VERSION 5.7 ;
  NOWIREEXTENSIONATPIN ON ;
  DIVIDERCHAR "/" ;
  BUSBITCHARS "[]" ;
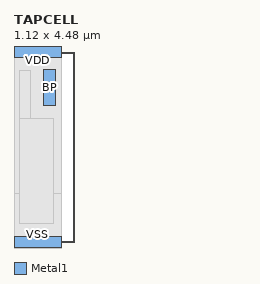
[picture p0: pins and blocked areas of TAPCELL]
MACRO TAPCELL
  CLASS core ;
  FOREIGN TAPCELL ;
  ORIGIN 0.000 0.000 ;
  SIZE 1.120 BY 4.480 ;
  SITE site056um ;
  PIN VSS
    DIRECTION INOUT ;
    USE GROUND ;
    PORT
      LAYER Metal1 ;
        RECT 0.000 -0.140 1.120 0.140 ;
    END
  END VSS
  PIN VDD
    DIRECTION INOUT ;
    USE POWER ;
    PORT
      LAYER Metal1 ;
        RECT 0.000 4.340 1.120 4.620 ;
    END
  END VDD
  PIN BP
    DIRECTION INPUT ;
    USE SIGNAL ;
    ANTENNADIFFAREA 0.298800 ;
    PORT
      LAYER Metal1 ;
        RECT 0.700 3.220 0.980 4.060 ;
    END
  END BP
  OBS
      LAYER Nwell ;
        RECT 0.000 1.135 1.120 4.755 ;
      LAYER Pwell ;
        RECT 0.000 -0.190 1.120 1.135 ;
      LAYER Metal1 ;
        RECT 0.140 2.920 0.400 4.040 ;
        RECT 0.140 0.440 0.940 2.920 ;
  END
END TAPCELL
END LIBRARY

